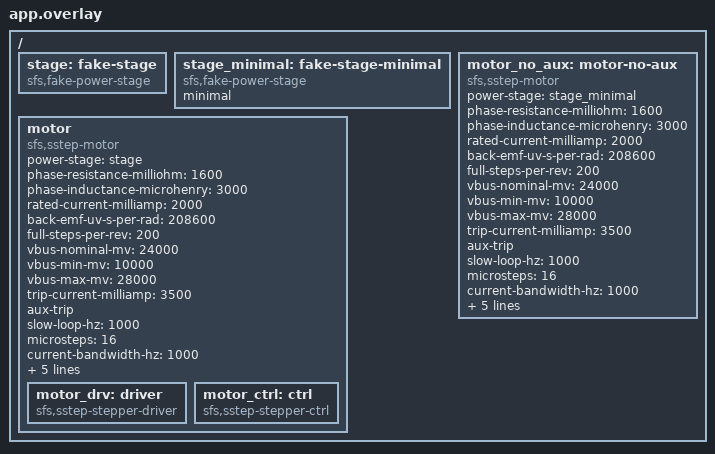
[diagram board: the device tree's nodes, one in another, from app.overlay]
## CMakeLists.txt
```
# SPDX-License-Identifier: Apache-2.0

cmake_minimum_required(VERSION 3.20.0)

list(APPEND DTS_ROOT "${CMAKE_CURRENT_LIST_DIR}/../common")

find_package(Zephyr REQUIRED HINTS $ENV{ZEPHYR_BASE})
project(test_sstep_motor LANGUAGES C)

# The motor suite fires every sample itself; with the self-test on, the load
# model of src/selftest.c fires them from a timer.
if(CONFIG_SSTEP_MOTOR_SELFTEST)
  target_sources(app PRIVATE src/selftest.c ../common/fake_power_stage.c)
else()
  target_sources(app PRIVATE src/main.c ../common/fake_power_stage.c)
endif()
if(CONFIG_SSTEP_MOTOR_MCUVIEWER)
  target_sources(app PRIVATE src/mcuviewer.c)
  target_include_directories(app PRIVATE ../../../drivers/motor)
endif()
target_include_directories(app PRIVATE ../common)
```

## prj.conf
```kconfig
# SPDX-License-Identifier: Apache-2.0

CONFIG_ZTEST=y
CONFIG_POWER_STAGE=y

# Every test case runs in its own thread: the one-caller check does not apply
CONFIG_SSTEP_MOTOR_THREAD_CHECK=n

# The motor suite fires every sample itself; the scenario .selftest turns it on
CONFIG_SSTEP_MOTOR_SELFTEST=n
```

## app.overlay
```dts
/*
 * SPDX-License-Identifier: Apache-2.0
 *
 * The motor driver on a fake power stage (ESC1 scaling), with the 17HS19-2004S1.
 */

/ {
	stage: fake-stage {
		compatible = "sfs,fake-power-stage";
	};

	stage_minimal: fake-stage-minimal {
		compatible = "sfs,fake-power-stage";
		minimal;
	};

	motor_no_aux: motor-no-aux {
		compatible = "sfs,sstep-motor";
		power-stage = <&stage_minimal>;
		phase-resistance-milliohm = <1600>;
		phase-inductance-microhenry = <3000>;
		rated-current-milliamp = <2000>;
		back-emf-uv-s-per-rad = <208600>;
		full-steps-per-rev = <200>;
		vbus-nominal-mv = <24000>;
		vbus-min-mv = <10000>;
		vbus-max-mv = <28000>;
		trip-current-milliamp = <3500>;
		aux-trip;
		slow-loop-hz = <1000>;
		microsteps = <16>;
		current-bandwidth-hz = <1000>;
		run-current-milliamp = <1500>;
		hold-current-milliamp = <500>;
		hold-delay-ms = <500>;
		max-velocity = <16000>;
		max-acceleration = <64000>;
	};

	motor: motor {
		compatible = "sfs,sstep-motor";
		power-stage = <&stage>;
		phase-resistance-milliohm = <1600>;
		phase-inductance-microhenry = <3000>;
		rated-current-milliamp = <2000>;
		back-emf-uv-s-per-rad = <208600>;
		full-steps-per-rev = <200>;
		vbus-nominal-mv = <24000>;
		vbus-min-mv = <10000>;
		vbus-max-mv = <28000>;
		trip-current-milliamp = <3500>;
		aux-trip;
		slow-loop-hz = <1000>;
		microsteps = <16>;
		current-bandwidth-hz = <1000>;
		run-current-milliamp = <1500>;
		hold-current-milliamp = <500>;
		hold-delay-ms = <500>;
		max-velocity = <16000>;
		max-acceleration = <64000>;

		motor_drv: driver {
			compatible = "sfs,sstep-stepper-driver";
		};

		motor_ctrl: ctrl {
			compatible = "sfs,sstep-stepper-ctrl";
		};
	};
};
```

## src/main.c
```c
/*
 * SPDX-License-Identifier: Apache-2.0
 *
 * Motor driver through the standard stepper classes, on a fake power stage: the
 * test fires the fast loop itself, so every step is deterministic.
 */

#include <errno.h>

#include <zephyr/drivers/stepper/stepper.h>
#include <zephyr/drivers/stepper/stepper_ctrl.h>
#include <zephyr/kernel.h>
#include <zephyr/ztest.h>

#include <doppelstep/drivers/sstep_motor.h>

#include "fake_power_stage.h"

static const struct device *const stage = DEVICE_DT_GET(DT_NODELABEL(stage));
static const struct device *const motor = DEVICE_DT_GET(DT_NODELABEL(motor));
static const struct device *const drv = DEVICE_DT_GET(DT_NODELABEL(motor_drv));
static const struct device *const ctrl = DEVICE_DT_GET(DT_NODELABEL(motor_ctrl));
static const struct device *const motor_no_aux = DEVICE_DT_GET(DT_NODELABEL(motor_no_aux));

/* 0 A on both phases at 24 V; 200 counts are above the trip level of 119 counts */
#define ADC_ZERO     2048U
#define ADC_VBUS_24V 2866U
#define ADC_OVER     (ADC_ZERO - 200U)

static const struct power_stage_sample zero = {ADC_ZERO, ADC_ZERO, ADC_VBUS_24V, ADC_ZERO};

static uint32_t steps_completed_events;
static uint32_t fault_events;
static uint32_t stall_events;

static void ctrl_event(const struct device *dev, const enum stepper_ctrl_event event, void *ud)
{
	ARG_UNUSED(dev);
	ARG_UNUSED(ud);
	if (event == STEPPER_CTRL_EVENT_STEPS_COMPLETED) {
		steps_completed_events++;
	}
}

static void drv_event(const struct device *dev, const enum stepper_event event, void *ud)
{
	ARG_UNUSED(dev);
	ARG_UNUSED(ud);
	if (event == STEPPER_EVENT_FAULT_DETECTED) {
		fault_events++;
	} else if (event == STEPPER_EVENT_STALL_DETECTED) {
		stall_events++;
	}
}

/* n slow-loop periods with their 20 fast-loop periods */
static void run_ms(uint32_t n)
{
	for (uint32_t k = 0U; k < n; k++) {
		for (uint32_t j = 0U; j < 20U; j++) {
			fake_power_stage_fire(stage, &zero, 0U);
		}
		zassert_ok(sstep_motor_process(motor));
	}
}

static struct sstep_motor_status status(void)
{
	struct sstep_motor_status st;

	zassert_ok(sstep_motor_get_status(motor, &st));
	return st;
}

static void before_each(void *fixture)
{
	const struct stepper_ctrl_ramp ramp = {
		.speed_max = 16000U,
		.acceleration_max = 64000U,
		.deceleration_max = 0U,
	};

	ARG_UNUSED(fixture);
	(void)stepper_disable(drv);
	(void)sstep_motor_clear_faults(motor);
	fake_power_stage_set_outputs_allowed(stage, true);
	zassert_ok(stepper_ctrl_configure_ramp(ctrl, &ramp));
	zassert_ok(stepper_ctrl_set_reference_position(ctrl, 0));
	zassert_ok(stepper_set_event_cb(drv, drv_event, NULL));
	zassert_ok(stepper_ctrl_set_event_cb(ctrl, ctrl_event, NULL));
	fake_power_stage_fire(stage, &zero, 0U); /* a bus voltage for the enable check */
	zassert_ok(sstep_motor_process(motor));
	steps_completed_events = 0U;
	fault_events = 0U;
	stall_events = 0U;
}

ZTEST(motor, test_devices_are_ready)
{
	zassert_true(device_is_ready(motor));
	zassert_true(device_is_ready(drv));
	zassert_true(device_is_ready(ctrl));
}

ZTEST(motor, test_aux_trip_on_a_stage_without_it_fails_at_init)
{
	/* The node asks for this overcurrent protection: losing it silently is not an option */
	zassert_false(device_is_ready(motor_no_aux));
}

ZTEST(motor, test_aux_trip_level_is_set_from_the_node)
{
	zassert_equal(fake_power_stage_aux_trip_ma(stage), 3500U);
}

ZTEST(motor, test_enable_is_refused_while_outputs_are_not_allowed)
{
	fake_power_stage_set_outputs_allowed(stage, false);
	zassert_equal(stepper_enable(drv), -EPERM);
	zassert_false(fake_power_stage_output_on(stage));
	run_ms(1);
	zassert_equal(status().state, SSTEP_MOTOR_DISABLED);
	zassert_equal(status().faults, 0U);
}

ZTEST(motor, test_enable_turns_outputs_on_and_holds)
{
	zassert_ok(stepper_enable(drv));
	zassert_true(fake_power_stage_output_on(stage));
	run_ms(1);
	zassert_equal(status().state, SSTEP_MOTOR_HOLDING);
	zassert_ok(stepper_disable(drv));
	zassert_false(fake_power_stage_output_on(stage));
	zassert_equal(status().state, SSTEP_MOTOR_DISABLED);
}

ZTEST(motor, test_move_reaches_the_target_and_reports_once)
{
	bool moving;
	int32_t pos;

	zassert_ok(stepper_enable(drv));
	zassert_ok(stepper_ctrl_move_to(ctrl, 3200));
	run_ms(1);
	zassert_ok(stepper_ctrl_is_moving(ctrl, &moving));
	zassert_true(moving);
	zassert_equal(status().target, 3200);
	run_ms(500);
	zassert_ok(stepper_ctrl_is_moving(ctrl, &moving));
	zassert_false(moving);
	zassert_ok(stepper_ctrl_get_actual_position(ctrl, &pos));
	zassert_equal(pos, 3200);
	zassert_equal(steps_completed_events, 1U);
}

ZTEST(motor, test_move_by_is_relative)
{
	int32_t pos;

	zassert_ok(stepper_enable(drv));
	zassert_ok(stepper_ctrl_move_to(ctrl, 800));
	run_ms(300);
	zassert_ok(stepper_ctrl_move_by(ctrl, -300));
	run_ms(300);
	zassert_ok(stepper_ctrl_get_actual_position(ctrl, &pos));
	zassert_equal(pos, 500);
}

ZTEST(motor, test_ramp_limits_the_speed_of_a_move)
{
	const struct stepper_ctrl_ramp slow = {
		.speed_max = 1000U,
		.acceleration_max = 64000U,
		.deceleration_max = 0U,
	};

	zassert_ok(stepper_enable(drv));
	zassert_ok(stepper_ctrl_configure_ramp(ctrl, &slow));
	zassert_ok(stepper_ctrl_move_to(ctrl, 3200));
	run_ms(1000);
	zassert_equal(status().velocity, 1000);
	zassert_within(status().position, 1000, 40);
}

ZTEST(motor, test_run_uses_the_ramp_speed_and_stop_ends_it)
{
	const struct stepper_ctrl_ramp ramp = {
		.speed_max = 3200U,
		.acceleration_max = 64000U,
		.deceleration_max = 0U,
	};
	bool moving;

	zassert_ok(stepper_enable(drv));
	zassert_ok(stepper_ctrl_configure_ramp(ctrl, &ramp));
	zassert_ok(stepper_ctrl_run(ctrl, STEPPER_CTRL_DIRECTION_NEGATIVE));
	run_ms(100);
	zassert_equal(status().velocity, -3200);
	zassert_ok(stepper_ctrl_stop(ctrl));
	run_ms(100);
	zassert_equal(status().velocity, 0);
	zassert_ok(stepper_ctrl_is_moving(ctrl, &moving));
	zassert_false(moving);
}

ZTEST(motor, test_microstep_interval_sets_the_speed_of_a_run)
{
	zassert_equal(stepper_ctrl_set_microstep_interval(ctrl, 0U), -EINVAL);
	zassert_ok(stepper_ctrl_set_microstep_interval(ctrl, 500000U)); /* 2000 microsteps/s */
	zassert_ok(stepper_enable(drv));
	zassert_ok(stepper_ctrl_run(ctrl, STEPPER_CTRL_DIRECTION_POSITIVE));
	run_ms(100);
	zassert_equal(status().velocity, 2000);
}

ZTEST(motor, test_zero_ramp_values_are_rejected)
{
	const struct stepper_ctrl_ramp no_speed = {.speed_max = 0U, .acceleration_max = 1000U};
	const struct stepper_ctrl_ramp no_accel = {.speed_max = 1000U, .acceleration_max = 0U};

	zassert_equal(stepper_ctrl_configure_ramp(ctrl, &no_speed), -EINVAL);
	zassert_equal(stepper_ctrl_configure_ramp(ctrl, &no_accel), -EINVAL);
}

ZTEST(motor, test_rejected_ramp_keeps_the_previous_one_and_stop_works)
{
	/* An acceleration below 8 microsteps/s^2 is below the resolution at 1 kHz */
	const struct stepper_ctrl_ramp too_low = {.speed_max = 1U, .acceleration_max = 1U};
	int32_t pos;

	zassert_ok(stepper_enable(drv));
	zassert_ok(stepper_ctrl_move_to(ctrl, 3200));
	run_ms(10);
	zassert_equal(stepper_ctrl_configure_ramp(ctrl, &too_low), -EINVAL);

	zassert_ok(stepper_ctrl_stop(ctrl));
	run_ms(500);
	zassert_equal(status().velocity, 0);
	zassert_ok(stepper_ctrl_get_actual_position(ctrl, &pos));
	zassert_true(pos < 3200, "the move must have been stopped, position %d", pos);
}

ZTEST(motor, test_stop_works_after_a_rejected_interval)
{
	int32_t pos;

	zassert_ok(stepper_enable(drv));
	zassert_ok(stepper_ctrl_move_to(ctrl, 3200));
	run_ms(10);
	zassert_equal(stepper_ctrl_set_microstep_interval(ctrl, UINT64_MAX), -EINVAL);

	zassert_ok(stepper_ctrl_stop(ctrl));
	run_ms(500);
	zassert_ok(stepper_ctrl_get_actual_position(ctrl, &pos));
	zassert_true(pos < 3200, "the move must have been stopped, position %d", pos);
}

ZTEST(motor, test_microstep_resolution_is_fixed)
{
	enum stepper_micro_step_resolution res;

	zassert_ok(stepper_set_micro_step_res(drv, STEPPER_MICRO_STEP_16));
	zassert_equal(stepper_set_micro_step_res(drv, STEPPER_MICRO_STEP_32), -ENOTSUP);
	zassert_ok(stepper_get_micro_step_res(drv, &res));
	zassert_equal(res, STEPPER_MICRO_STEP_16);
}

ZTEST(motor, test_overcurrent_stops_outputs_inside_the_fast_loop)
{
	const struct power_stage_sample over = {ADC_OVER, ADC_ZERO, ADC_VBUS_24V};
	struct sstep_motor_status st;

	zassert_ok(stepper_enable(drv));
	run_ms(1);
	fake_power_stage_fire(stage, &over, 0U);
	zassert_false(fake_power_stage_output_on(stage));
	zassert_equal(fault_events, 0U, "events must not come from the interrupt context");

	zassert_ok(sstep_motor_process(motor));
	zassert_equal(fault_events, 1U);
	st = status();
	zassert_equal(st.state, SSTEP_MOTOR_FAULT);
	zassert_true((st.faults & SSTEP_MOTOR_FAULT_OVERCURRENT) != 0U);

	zassert_ok(sstep_motor_process(motor));
	zassert_equal(fault_events, 1U, "one event per new fault");
}

ZTEST(motor, test_aux_trip_reports_external_fault)
{
	zassert_ok(stepper_enable(drv));
	run_ms(1);
	fake_power_stage_fire(stage, &zero, POWER_STAGE_TRIP_AUX);
	zassert_false(fake_power_stage_output_on(stage));
	zassert_ok(sstep_motor_process(motor));
	zassert_true((status().faults & SSTEP_MOTOR_FAULT_EXTERNAL) != 0U);
}

ZTEST(motor, test_hw_overcurrent_trip_latches_overcurrent)
{
	zassert_ok(stepper_enable(drv));
	run_ms(1);
	fake_power_stage_fire(stage, &zero, POWER_STAGE_TRIP_HW_OC);
	zassert_false(fake_power_stage_output_on(stage));
	zassert_ok(sstep_motor_process(motor));
	zassert_equal(status().state, SSTEP_MOTOR_FAULT);
	zassert_true((status().faults & SSTEP_MOTOR_FAULT_OVERCURRENT) != 0U);
}

ZTEST(motor, test_hw_overvoltage_trip_latches_overvoltage)
{
	zassert_ok(stepper_enable(drv));
	run_ms(1);
	fake_power_stage_fire(stage, &zero, POWER_STAGE_TRIP_HW_OV);
	zassert_false(fake_power_stage_output_on(stage));
	zassert_ok(sstep_motor_process(motor));
	zassert_equal(status().state, SSTEP_MOTOR_FAULT);
	zassert_true((status().faults & SSTEP_MOTOR_FAULT_OVERVOLTAGE) != 0U);
}

ZTEST(motor, test_fast_loop_overrun_reports_a_hal_fault)
{
	zassert_ok(stepper_enable(drv));
	run_ms(1);
	zassert_true(fake_power_stage_output_on(stage));
	fake_power_stage_fire(stage, &zero, POWER_STAGE_TRIP_OVERRUN);
	zassert_false(fake_power_stage_output_on(stage), "the fault keeps the outputs off");
	zassert_ok(sstep_motor_process(motor));
	zassert_equal(status().state, SSTEP_MOTOR_FAULT);
	zassert_true((status().faults & SSTEP_MOTOR_FAULT_HAL) != 0U);
	zassert_true((status().faults & SSTEP_MOTOR_FAULT_EXTERNAL) == 0U,
		     "an overrun is not an overcurrent");
}

/* A flash write of the EEPROM area (allowed only with the torque off) stalls the CPU
 * for many PWM periods: harmless with the outputs off, so no fault may latch.
 */
ZTEST(motor, test_fast_loop_overrun_with_the_outputs_off_is_ignored)
{
	zassert_false(fake_power_stage_output_on(stage));
	fake_power_stage_fire(stage, &zero, POWER_STAGE_TRIP_OVERRUN);
	zassert_ok(sstep_motor_process(motor));
	zassert_equal(status().faults, 0U);
	zassert_ok(stepper_enable(drv), "Torque Enable still works");
	run_ms(1);
	zassert_true(fake_power_stage_output_on(stage));
}

ZTEST(motor, test_undervoltage_is_reported)
{
	const struct power_stage_sample low = {ADC_ZERO, ADC_ZERO, 1000U}; /* 8.4 V */

	zassert_ok(stepper_enable(drv));
	run_ms(1);
	fake_power_stage_fire(stage, &low, 0U);
	zassert_ok(sstep_motor_process(motor));
	zassert_true((status().faults & SSTEP_MOTOR_FAULT_UNDERVOLTAGE) != 0U);
}

ZTEST(motor, test_enable_in_a_fault_is_rejected_until_cleared)
{
	const struct power_stage_sample over = {ADC_OVER, ADC_ZERO, ADC_VBUS_24V};

	zassert_ok(stepper_enable(drv));
	run_ms(1);
	fake_power_stage_fire(stage, &over, 0U);
	zassert_ok(sstep_motor_process(motor));
	zassert_equal(stepper_enable(drv), -EBUSY);

	zassert_ok(sstep_motor_clear_faults(motor));
	zassert_equal(status().state, SSTEP_MOTOR_DISABLED);
	zassert_equal(status().faults, 0U);
	zassert_ok(stepper_enable(drv));

	/* a second fault after clearing is a new event */
	fake_power_stage_fire(stage, &over, 0U);
	zassert_ok(sstep_motor_process(motor));
	zassert_equal(fault_events, 2U);
}

ZTEST(motor, test_reference_position_is_rejected_while_moving)
{
	zassert_ok(stepper_enable(drv));
	zassert_ok(stepper_ctrl_move_to(ctrl, 3200));
	run_ms(10);
	zassert_equal(stepper_ctrl_set_reference_position(ctrl, 0), -EBUSY);
}

ZTEST(motor, test_reference_position_notifies_the_power_stage)
{
	const int32_t before = fake_power_stage_shift_total(stage);
	int32_t pos;

	zassert_ok(stepper_ctrl_set_reference_position(ctrl, 700));
	zassert_equal(fake_power_stage_shift_total(stage) - before, 700);
	zassert_ok(stepper_ctrl_get_actual_position(ctrl, &pos));
	zassert_equal(pos, 700);
}

ZTEST(motor, test_set_current_is_limited_to_the_node_values)
{
	struct sstep_motor_status st;

	zassert_ok(sstep_motor_set_current(motor, 5000U, 5000U));
	st = status();
	zassert_equal(st.i_run_ma, 1500U);
	zassert_equal(st.i_hold_ma, 500U);

	zassert_ok(sstep_motor_set_current(motor, 300U, 500U));
	st = status();
	zassert_equal(st.i_run_ma, 300U);
	zassert_equal(st.i_hold_ma, 300U, "hold never above run");

	zassert_ok(sstep_motor_set_current(motor, 1500U, 500U));
}

ZTEST(motor, test_status_amplitude_is_the_averaged_root_of_both_phases)
{
	/* 10 and 14 counts of 2048 at 60155 mA: 294 mA and 411 mA */
	const struct power_stage_sample s = {ADC_ZERO - 10U, ADC_ZERO - 14U, ADC_VBUS_24V, ADC_ZERO};
	uint32_t first;

	zassert_ok(stepper_enable(drv));
	fake_power_stage_fire(stage, &s, 0U);
	first = status().i_amplitude_ma;
	zassert_within(first, 505U / 8U, 10U, "one call: an eighth (%u mA)", first);
	for (int k = 0; k < 60; k++) {
		fake_power_stage_fire(stage, &s, 0U);
		(void)status();
	}
	zassert_within(status().i_amplitude_ma, 505U, 10U, "%u mA", status().i_amplitude_ma);
}

ZTEST(motor, test_status_amplitude_is_zero_with_the_outputs_off)
{
	const struct power_stage_sample s = {ADC_ZERO - 10U, ADC_ZERO - 14U, ADC_VBUS_24V, ADC_ZERO};

	fake_power_stage_fire(stage, &s, 0U);
	zassert_equal(status().i_amplitude_ma, 0U, "sensor offset with no current flowing");
}

ZTEST(motor, test_status_reports_the_bus_voltage)
{
	fake_power_stage_fire(stage, &zero, 0U);
	zassert_within(status().vbus_mv, 24000U, 20U);
}

ZTEST(motor, test_enable_with_vbus_out_of_range_is_refused)
{
	const struct power_stage_sample low = {ADC_ZERO, ADC_ZERO, 955U, ADC_ZERO}; /* 8 V */

	fake_power_stage_fire(stage, &low, 0U);
	zassert_equal(stepper_enable(drv), -ERANGE);
	zassert_false(fake_power_stage_output_on(stage));
	zassert_equal(status().state, SSTEP_MOTOR_DISABLED, "not latched");
	zassert_equal(status().faults, 0U);
	fake_power_stage_fire(stage, &zero, 0U);
	zassert_ok(stepper_enable(drv), "works once the supply is back");
}

ZTEST_SUITE(motor, NULL, NULL, before_each, NULL, NULL);
```

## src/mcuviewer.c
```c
/*
 * SPDX-License-Identifier: Apache-2.0
 *
 * MCUViewer variables of the motor driver (scenario .mcuviewer): scaling of the
 * currents and the phase voltages, averages, peak-to-peak window and capture buffer.
 * The motor without aux trip fails at init, so the motor `motor` owns the probe.
 */

#include <stdlib.h>

#include <zephyr/drivers/stepper/stepper.h>
#include <zephyr/kernel.h>
#include <zephyr/ztest.h>

#include <doppelstep/drivers/sstep_motor.h>

#include "fake_power_stage.h"
#include "sstep_mcuviewer.h"

static const struct device *const stage = DEVICE_DT_GET(DT_NODELABEL(stage));
static const struct device *const motor = DEVICE_DT_GET(DT_NODELABEL(motor));
static const struct device *const drv = DEVICE_DT_GET(DT_NODELABEL(motor_drv));

/* Scaling of the fake stage */
#define ADC_ZERO     2048
#define ADC_VBUS_24V 2866U
#define I_FS_MA      60155
#define I_SPAN       (-2048)
#define VBUS_FULL_MV 34283
#define ADC_FULL     4095
#define PERIOD       4250

static int32_t counts_to_ma(int32_t counts)
{
	return (int32_t)(((int64_t)counts * I_FS_MA) / I_SPAN);
}

static const int32_t vbus_mv = (int32_t)(((int64_t)ADC_VBUS_24V * VBUS_FULL_MV) / ADC_FULL);

static void fire(int32_t da, int32_t db)
{
	const struct power_stage_sample s = {
		.i_a = (uint16_t)(ADC_ZERO + da),
		.i_b = (uint16_t)(ADC_ZERO + db),
		.vbus = ADC_VBUS_24V,
		.i_aux = (uint16_t)(ADC_ZERO - da - db),
	};

	fake_power_stage_fire(stage, &s, 0U);
}

static void before_each(void *fixture)
{
	ARG_UNUSED(fixture);
	(void)stepper_disable(drv);
	(void)sstep_motor_clear_faults(motor);
	fake_power_stage_set_outputs_allowed(stage, true);
	mcuv.capture_arm = 0U;
	fire(0, 0); /* ends a capture that a test left running */
	fire(0, 0); /* a bus voltage for the enable check */
	zassert_ok(sstep_motor_process(motor));
}

ZTEST(mcuviewer, test_header_describes_the_stage)
{
	zassert_equal(mcuv.magic, SSTEP_MCUV_MAGIC);
	zassert_equal(mcuv.version, SSTEP_MCUV_VERSION);
	zassert_equal(mcuv.pwm_freq_hz, 20000U);
	zassert_equal(mcuv.shared_leg, 1U);
	zassert_equal(mcuv.window_periods, 2000U, "100 ms");
	zassert_equal(mcuv.capture_length, CONFIG_SSTEP_MOTOR_MCUVIEWER_SAMPLES);
}

ZTEST(mcuviewer, test_currents_and_bus_voltage_are_in_engineering_units)
{
	const uint32_t periods = mcuv.periods;

	fire(-100, 40);
	zassert_equal(mcuv.periods, periods + 1U);
	zassert_within(mcuv.i_a_ma, counts_to_ma(-100), 1);
	zassert_within(mcuv.i_b_ma, counts_to_ma(40), 1);
	zassert_within(mcuv.i_w_ma, counts_to_ma(60), 1);
	zassert_within(mcuv.vbus_mv, vbus_mv, 1);
	zassert_true(mcuv.i_a_ma > 0, "-100 counts are +2.9 A with the negative span");
}

ZTEST(mcuviewer, test_phase_voltage_is_zero_with_the_outputs_off)
{
	fire(0, 0);
	zassert_equal(mcuv.outputs_on, 0U);
	zassert_equal(mcuv.v_a_mv, 0);
	zassert_equal(mcuv.v_b_mv, 0);
}

ZTEST(mcuviewer, test_phase_voltage_follows_the_compares_of_the_sampled_period)
{
	zassert_ok(stepper_enable(drv));
	for (int k = 0; k < 200; k++) {
		fire(0, 0); /* no current: the loop drives a voltage towards the hold current */
	}

	const uint16_t *cmp = fake_power_stage_compare(stage);
	const int32_t da = (int32_t)cmp[0] - (int32_t)cmp[2];
	const int32_t db = (int32_t)cmp[1] - (int32_t)cmp[2];

	fire(0, 0);
	zassert_equal(mcuv.outputs_on, 1U);
	zassert_within(mcuv.v_a_mv, (da * vbus_mv) / PERIOD, 2);
	zassert_within(mcuv.v_b_mv, (db * vbus_mv) / PERIOD, 2);
	zassert_true((abs(mcuv.v_a_mv) + abs(mcuv.v_b_mv)) > 1000, "the loop drives a voltage");
	zassert_ok(stepper_disable(drv));
}

ZTEST(mcuviewer, test_average_settles_on_a_constant_current)
{
	for (int k = 0; k < 4000; k++) {
		fire(-50, 0);
	}
	zassert_within(mcuv.i_a_avg_ma, counts_to_ma(-50), 2);
	zassert_within(mcuv.i_b_avg_ma, 0, 2);
}

ZTEST(mcuviewer, test_peak_to_peak_over_a_window)
{
	/* Two full windows: the second one only sees the toggle by one count */
	for (uint32_t k = 0U; k < 2U * mcuv.window_periods; k++) {
		fire(((k & 1U) != 0U) ? -1 : 0, 3);
	}
	zassert_within(mcuv.i_a_pp_ma, abs(counts_to_ma(1)), 1);
	zassert_equal(mcuv.i_b_pp_ma, 0);
}

ZTEST(mcuviewer, test_capture_records_every_nth_period_and_stops_when_full)
{
	const uint32_t n = mcuv.capture_length;

	mcuv.capture_divider = 2U;
	mcuv.capture_arm = 1U;
	for (uint32_t k = 0U; k < 2U * n + 10U; k++) {
		fire(-(int32_t)k, 0);
	}
	zassert_equal(mcuv.capture_arm, 0U, "the buffer is full");
	zassert_equal(mcuv.capture_count, n);
	zassert_equal(mcuv.capture_rate_hz, 10000U);
	zassert_within(mcuv_buf[0].i_a_ma, counts_to_ma(0), 1);
	zassert_within(mcuv_buf[1].i_a_ma, counts_to_ma(-2), 1);
	zassert_within(mcuv_buf[5].i_a_ma, counts_to_ma(-10), 1);
	mcuv.capture_divider = 1U;
}

ZTEST(mcuviewer, test_capture_saturates_to_16_bits)
{
	mcuv.capture_divider = 1U;
	mcuv.capture_arm = 1U;
	fire(-2000, 0); /* about 58.8 A: beyond int16 in mA */
	zassert_equal(mcuv_buf[0].i_a_ma, INT16_MAX);
	zassert_true(mcuv.i_a_ma > INT16_MAX, "the live value is not saturated");
	mcuv.capture_arm = 0U;
}

ZTEST_SUITE(mcuviewer, NULL, NULL, before_each, NULL, NULL);
```

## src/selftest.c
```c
/*
 * SPDX-License-Identifier: Apache-2.0
 *
 * The self-test and the bus voltage check of stepper_enable(), on the fake power
 * stage with a resistive load model fired by a timer (scenario .selftest).
 * stepper_enable() starts the test and returns; the slow loop ends it, as the
 * control task does every millisecond.
 */

#include <errno.h>

#include <zephyr/drivers/stepper/stepper.h>
#include <zephyr/drivers/stepper/stepper_ctrl.h>
#include <zephyr/kernel.h>
#include <zephyr/ztest.h>

#include <doppelstep/drivers/sstep_motor.h>

#include "fake_power_stage.h"

static const struct device *const stage = DEVICE_DT_GET(DT_NODELABEL(stage));
static const struct device *const motor = DEVICE_DT_GET(DT_NODELABEL(motor));
static const struct device *const drv = DEVICE_DT_GET(DT_NODELABEL(motor_drv));
static const struct device *const ctrl = DEVICE_DT_GET(DT_NODELABEL(motor_ctrl));

#define PERIOD   4250
#define ZERO     2048
#define I_FS_MA  60155 /* scaling of the fake stage */
#define R_MOHM   1600
#define VBUS_24V 2866U
#define VBUS_8V  955U

/* Coil currents follow the coil voltage with the time constant of the winding,
 * L / R = 3 mH / 1.6 Ohm, about 38 PWM periods (first order, no dead time): the self-test
 * and, after it, the current loop of Stepper-C act on it as on the motor.
 */
#define TAU_PERIODS 38
struct load {
	bool open_a;
	bool dead_w_sensor; /* the shunt of the shared leg reads 0 A */
	bool w_spike;       /* one sample of the shared leg 80 counts off (a switching edge) */
	uint32_t samples;
	uint16_t vbus;
	uint32_t periods_a; /* periods with coil A driven */
	uint32_t periods_b;
	bool outputs_seen;
	int32_t ia_ma; /* coil currents of the model */
	int32_t ib_ma;
};

static struct load load;

static uint16_t counts(int32_t i_ma)
{
	return (uint16_t)(ZERO + i_ma * -2048 / I_FS_MA);
}

static void plant(const uint16_t *cmp, bool on, struct power_stage_sample *out, void *ctx)
{
	struct load *l = ctx;
	const int32_t vbus_mv = l->vbus * 34283 / 4095;
	int32_t ia_ss = 0; /* steady-state currents of this voltage */
	int32_t ib_ss = 0;
	int32_t ia;
	int32_t ib;

	if (on) {
		l->outputs_seen = true;
		if (!l->open_a) {
			ia_ss = ((int32_t)cmp[0] - cmp[2]) * vbus_mv / PERIOD * 1000 / R_MOHM;
		}
		ib_ss = ((int32_t)cmp[1] - cmp[2]) * vbus_mv / PERIOD * 1000 / R_MOHM;
		l->periods_a += (cmp[0] > 0U) ? 1U : 0U;
		l->periods_b += (cmp[1] > 0U) ? 1U : 0U;
		l->ia_ma += (ia_ss - l->ia_ma) / TAU_PERIODS;
		l->ib_ma += (ib_ss - l->ib_ma) / TAU_PERIODS;
	} else {
		l->ia_ma = 0; /* outputs off: the current decays within a period */
		l->ib_ma = 0;
	}
	if (l->open_a) {
		l->ia_ma = 0;
	}
	ia = l->ia_ma;
	ib = l->ib_ma;
	out->i_a = counts(ia);
	out->i_b = counts(ib);
	out->i_aux = l->dead_w_sensor ? counts(0) : counts(-(ia + ib));
	l->samples++;
	if (l->w_spike && (l->samples == 400U)) {
		out->i_aux -= 80U;
	}
	out->vbus = l->vbus;
}

static struct sstep_motor_status status(void)
{
	struct sstep_motor_status st;

	zassert_ok(sstep_motor_get_status(motor, &st));
	return st;
}

/* 150 slow-loop periods: more than the self-test timeout (100) */
static void settle(void)
{
	for (int ms = 0; ms < 150; ms++) {
		(void)sstep_motor_process(motor);
		k_sleep(K_MSEC(1));
	}
}

static void before_each(void *fixture)
{
	ARG_UNUSED(fixture);
	fake_power_stage_set_plant(stage, NULL, NULL);
	(void)stepper_disable(drv);
	(void)sstep_motor_clear_faults(motor);
	fake_power_stage_set_outputs_allowed(stage, true);
	load = (struct load){.vbus = VBUS_24V};
	fake_power_stage_set_plant(stage, plant, &load);
	k_sleep(K_MSEC(5)); /* a bus voltage reading */
}

static void after_each(void *fixture)
{
	ARG_UNUSED(fixture);
	(void)stepper_disable(drv);
	fake_power_stage_set_plant(stage, NULL, NULL);
}

ZTEST(motor_selftest, test_enable_answers_before_the_selftest_ends)
{
	/* A DYNAMIXEL host waits about 34 ms for the answer to Torque Enable */
	zassert_ok(stepper_enable(drv));
	zassert_equal(load.periods_b, 0U, "returned before coil B was tested");
	zassert_equal(status().state, SSTEP_MOTOR_HOLDING, "torque on while the test runs");
	zassert_ok(stepper_enable(drv), "a second enable meanwhile is accepted");

	settle();
	zassert_true(load.periods_a > 0U, "coil A tested");
	zassert_true(load.periods_b > 0U, "coil B tested");
	zassert_true(fake_power_stage_output_on(stage), "Stepper-C runs after the test");
	zassert_equal(status().state, SSTEP_MOTOR_HOLDING);
	zassert_equal(status().faults, 0U);
}

ZTEST(motor_selftest, test_enable_runs_the_selftest_once)
{
	zassert_ok(stepper_enable(drv));
	settle();
	zassert_ok(stepper_disable(drv));
	load = (struct load){.vbus = VBUS_24V};
	zassert_ok(stepper_enable(drv));
	zassert_equal(load.periods_a + load.periods_b, 0U, "only at the first enable");
	zassert_true(fake_power_stage_output_on(stage));
	zassert_equal(status().faults, 0U);
}

ZTEST(motor_selftest, test_motion_during_the_selftest_runs_after_it)
{
	zassert_ok(stepper_enable(drv));
	zassert_ok(stepper_ctrl_move_to(ctrl, 1000), "accepted while the test runs");
	zassert_equal(status().target, status().position, "not started yet");
	settle();
	zassert_equal(status().target, 1000, "executed after the test passed");
	zassert_equal(status().faults, 0U);
}

ZTEST(motor_selftest, test_disable_during_the_selftest_stops_it)
{
	zassert_ok(stepper_enable(drv));
	zassert_ok(stepper_disable(drv));
	load.periods_b = 0U;
	settle();
	zassert_equal(load.periods_b, 0U, "the test does not go on");
	zassert_false(fake_power_stage_output_on(stage));
	zassert_equal(status().state, SSTEP_MOTOR_DISABLED);
	zassert_equal(status().faults, 0U, "not a fault");
}

ZTEST(motor_selftest, test_failed_selftest_latches_a_fault)
{
	load.open_a = true;
	zassert_ok(stepper_enable(drv), "accepted, as an XM430 accepts Torque Enable");
	settle();
	zassert_false(fake_power_stage_output_on(stage));
	zassert_equal(status().state, SSTEP_MOTOR_FAULT);
	zassert_true((status().faults & SSTEP_MOTOR_FAULT_SELFTEST) != 0U);

	/* Latched: no second test into a broken bridge */
	load.periods_a = 0U;
	zassert_not_equal(stepper_enable(drv), 0);
	settle();
	zassert_equal(load.periods_a, 0U);
	zassert_false(fake_power_stage_output_on(stage));

	/* After clearing (a Reboot in the application) the test runs again */
	zassert_ok(sstep_motor_clear_faults(motor));
	load = (struct load){.vbus = VBUS_24V};
	zassert_ok(stepper_enable(drv));
	settle();
	zassert_true(load.periods_a > 0U);
	zassert_true(fake_power_stage_output_on(stage));
}

ZTEST(motor_selftest, test_broken_sensor_of_the_shared_leg_fails)
{
	/* Stepper-C sees iU and iV only; the driver adds up the three legs */
	load.dead_w_sensor = true;
	zassert_ok(stepper_enable(drv));
	settle();
	zassert_false(fake_power_stage_output_on(stage));
	zassert_equal(status().state, SSTEP_MOTOR_FAULT);
	zassert_true((status().faults & SSTEP_MOTOR_FAULT_SELFTEST) != 0U);
}

ZTEST(motor_selftest, test_one_disturbed_sample_of_the_shared_leg_passes)
{
	/* a broken sensor is wrong as long as current flows; one disturbed sample is not */
	load.w_spike = true;
	zassert_ok(stepper_enable(drv));
	settle();
	zassert_true(load.samples > 400U, "the disturbed sample came during the test");
	zassert_true(fake_power_stage_output_on(stage));
	zassert_equal(status().faults, 0U);
}

ZTEST(motor_selftest, test_enable_with_vbus_out_of_range_is_refused)
{
	load.vbus = VBUS_8V;
	k_sleep(K_MSEC(5));
	load.outputs_seen = false;
	zassert_equal(stepper_enable(drv), -ERANGE);
	zassert_false(load.outputs_seen, "nothing energised before the voltage is checked");
	zassert_equal(status().faults, 0U, "not latched");
}

ZTEST_SUITE(motor_selftest, NULL, NULL, before_each, after_each, NULL);
```
